# sar_afe_r.lef -- ADC analog front end hard macro (generated 2026-10-20)
# Generated by analog/cadence/pv/macro/export_macro.sh; do not edit.
VERSION 5.8 ;
BUSBITCHARS "[]" ;
DIVIDERCHAR "/" ;

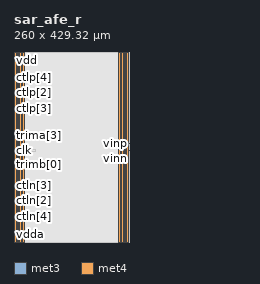
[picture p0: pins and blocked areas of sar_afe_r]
MACRO sar_afe_r
  CLASS BLOCK ;
  FOREIGN sar_afe_r 0 0 ;
  ORIGIN 0 0 ;
  SIZE 260.000 BY 429.320 ;
  SYMMETRY X Y ;
  PIN clk
    DIRECTION INPUT ;
    USE SIGNAL ;
    ANTENNAGATEAREA 1.5000 ;
    PORT
      LAYER met3 ;
        RECT 0.000 206.860 0.600 207.260 ;
    END
  END clk
  PIN ctln[0]
    DIRECTION INPUT ;
    USE SIGNAL ;
    ANTENNAGATEAREA 0.1455 ;
    PORT
      LAYER met3 ;
        RECT 0.000 101.460 0.600 101.860 ;
    END
  END ctln[0]
  PIN ctln[1]
    DIRECTION INPUT ;
    USE SIGNAL ;
    ANTENNAGATEAREA 0.1455 ;
    PORT
      LAYER met3 ;
        RECT 0.000 100.100 0.600 100.500 ;
    END
  END ctln[1]
  PIN ctln[2]
    DIRECTION INPUT ;
    USE SIGNAL ;
    ANTENNAGATEAREA 0.1455 ;
    PORT
      LAYER met3 ;
        RECT 0.000 92.620 0.600 93.020 ;
    END
  END ctln[2]
  PIN ctln[3]
    DIRECTION INPUT ;
    USE SIGNAL ;
    ANTENNAGATEAREA 0.1455 ;
    PORT
      LAYER met3 ;
        RECT 0.000 108.940 0.600 109.340 ;
    END
  END ctln[3]
  PIN ctln[4]
    DIRECTION INPUT ;
    USE SIGNAL ;
    ANTENNAGATEAREA 0.1455 ;
    PORT
      LAYER met3 ;
        RECT 0.000 75.620 0.600 76.020 ;
    END
  END ctln[4]
  PIN ctln[5]
    DIRECTION INPUT ;
    USE SIGNAL ;
    ANTENNAGATEAREA 0.1455 ;
    PORT
      LAYER met3 ;
        RECT 0.000 117.100 0.600 117.500 ;
    END
  END ctln[5]
  PIN ctln[6]
    DIRECTION INPUT ;
    USE SIGNAL ;
    ANTENNAGATEAREA 0.1455 ;
    PORT
      LAYER met3 ;
        RECT 0.000 125.940 0.600 126.340 ;
    END
  END ctln[6]
  PIN ctln[7]
    DIRECTION INPUT ;
    USE SIGNAL ;
    ANTENNAGATEAREA 0.1455 ;
    PORT
      LAYER met3 ;
        RECT 0.000 134.780 0.600 135.180 ;
    END
  END ctln[7]
  PIN ctlp[0]
    DIRECTION INPUT ;
    USE SIGNAL ;
    ANTENNAGATEAREA 0.1455 ;
    PORT
      LAYER met3 ;
        RECT 0.000 327.900 0.600 328.300 ;
    END
  END ctlp[0]
  PIN ctlp[1]
    DIRECTION INPUT ;
    USE SIGNAL ;
    ANTENNAGATEAREA 0.1455 ;
    PORT
      LAYER met3 ;
        RECT 0.000 329.260 0.600 329.660 ;
    END
  END ctlp[1]
  PIN ctlp[2]
    DIRECTION INPUT ;
    USE SIGNAL ;
    ANTENNAGATEAREA 0.1455 ;
    PORT
      LAYER met3 ;
        RECT 0.000 336.740 0.600 337.140 ;
    END
  END ctlp[2]
  PIN ctlp[3]
    DIRECTION INPUT ;
    USE SIGNAL ;
    ANTENNAGATEAREA 0.1455 ;
    PORT
      LAYER met3 ;
        RECT 0.000 319.740 0.600 320.140 ;
    END
  END ctlp[3]
  PIN ctlp[4]
    DIRECTION INPUT ;
    USE SIGNAL ;
    ANTENNAGATEAREA 0.1455 ;
    PORT
      LAYER met3 ;
        RECT 0.000 353.060 0.600 353.460 ;
    END
  END ctlp[4]
  PIN ctlp[5]
    DIRECTION INPUT ;
    USE SIGNAL ;
    ANTENNAGATEAREA 0.1455 ;
    PORT
      LAYER met3 ;
        RECT 0.000 311.580 0.600 311.980 ;
    END
  END ctlp[5]
  PIN ctlp[6]
    DIRECTION INPUT ;
    USE SIGNAL ;
    ANTENNAGATEAREA 0.1455 ;
    PORT
      LAYER met3 ;
        RECT 0.000 302.740 0.600 303.140 ;
    END
  END ctlp[6]
  PIN ctlp[7]
    DIRECTION INPUT ;
    USE SIGNAL ;
    ANTENNAGATEAREA 0.1455 ;
    PORT
      LAYER met3 ;
        RECT 0.000 293.900 0.600 294.300 ;
    END
  END ctlp[7]
  PIN outn
    DIRECTION OUTPUT ;
    USE SIGNAL ;
    ANTENNAGATEAREA 0.6000 ;
    ANTENNADIFFAREA 0.7950 ;
    PORT
      LAYER met3 ;
        RECT 0.000 217.740 0.600 218.140 ;
    END
  END outn
  PIN outp
    DIRECTION OUTPUT ;
    USE SIGNAL ;
    ANTENNAGATEAREA 0.6000 ;
    ANTENNADIFFAREA 0.7950 ;
    PORT
      LAYER met3 ;
        RECT 0.000 211.620 0.600 212.020 ;
    END
  END outp
  PIN sample
    DIRECTION INPUT ;
    USE SIGNAL ;
    ANTENNAGATEAREA 0.5110 ;
    PORT
      LAYER met3 ;
        RECT 0.000 253.100 0.600 253.500 ;
    END
  END sample
  PIN trima[0]
    DIRECTION INPUT ;
    USE SIGNAL ;
    ANTENNAGATEAREA 0.3000 ;
    PORT
      LAYER met3 ;
        RECT 0.000 236.780 0.600 237.180 ;
    END
  END trima[0]
  PIN trima[1]
    DIRECTION INPUT ;
    USE SIGNAL ;
    ANTENNAGATEAREA 0.3000 ;
    PORT
      LAYER met3 ;
        RECT 0.000 238.140 0.600 238.540 ;
    END
  END trima[1]
  PIN trima[2]
    DIRECTION INPUT ;
    USE SIGNAL ;
    ANTENNAGATEAREA 0.3000 ;
    PORT
      LAYER met3 ;
        RECT 0.000 239.500 0.600 239.900 ;
    END
  END trima[2]
  PIN trima[3]
    DIRECTION INPUT ;
    USE SIGNAL ;
    ANTENNAGATEAREA 0.3000 ;
    PORT
      LAYER met3 ;
        RECT 0.000 240.860 0.600 241.260 ;
    END
  END trima[3]
  PIN trima[4]
    DIRECTION INPUT ;
    USE SIGNAL ;
    ANTENNAGATEAREA 0.3000 ;
    PORT
      LAYER met3 ;
        RECT 0.000 242.220 0.600 242.620 ;
    END
  END trima[4]
  PIN trimb[0]
    DIRECTION INPUT ;
    USE SIGNAL ;
    ANTENNAGATEAREA 0.3000 ;
    PORT
      LAYER met3 ;
        RECT 0.000 191.900 0.600 192.300 ;
    END
  END trimb[0]
  PIN trimb[1]
    DIRECTION INPUT ;
    USE SIGNAL ;
    ANTENNAGATEAREA 0.3000 ;
    PORT
      LAYER met3 ;
        RECT 0.000 190.540 0.600 190.940 ;
    END
  END trimb[1]
  PIN trimb[2]
    DIRECTION INPUT ;
    USE SIGNAL ;
    ANTENNAGATEAREA 0.3000 ;
    PORT
      LAYER met3 ;
        RECT 0.000 189.180 0.600 189.580 ;
    END
  END trimb[2]
  PIN trimb[3]
    DIRECTION INPUT ;
    USE SIGNAL ;
    ANTENNAGATEAREA 0.3000 ;
    PORT
      LAYER met3 ;
        RECT 0.000 187.820 0.600 188.220 ;
    END
  END trimb[3]
  PIN trimb[4]
    DIRECTION INPUT ;
    USE SIGNAL ;
    ANTENNAGATEAREA 0.3000 ;
    PORT
      LAYER met3 ;
        RECT 0.000 186.460 0.600 186.860 ;
    END
  END trimb[4]
  PIN vdd
    DIRECTION INOUT ;
    USE POWER ;
    PORT
      LAYER met4 ;
        RECT 19.000 0.000 23.000 429.320 ;
    END
    PORT
      LAYER met4 ;
        RECT 237.000 0.000 241.000 429.320 ;
    END
  END vdd
  PIN vdda
    DIRECTION INOUT ;
    USE POWER ;
    PORT
      LAYER met4 ;
        RECT 7.000 0.000 11.000 429.320 ;
    END
    PORT
      LAYER met4 ;
        RECT 249.000 0.000 253.000 429.320 ;
    END
  END vdda
  PIN vinn
    DIRECTION INPUT ;
    USE SIGNAL ;
    ANTENNADIFFAREA 0.5300 ;
    PORT
      LAYER met3 ;
        RECT 259.400 207.310 260.000 207.710 ;
    END
  END vinn
  PIN vinp
    DIRECTION INPUT ;
    USE SIGNAL ;
    ANTENNADIFFAREA 0.5300 ;
    PORT
      LAYER met3 ;
        RECT 259.400 221.610 260.000 222.010 ;
    END
  END vinp
  PIN vref
    DIRECTION INOUT ;
    USE POWER ;
    PORT
      LAYER met4 ;
        RECT 13.000 0.000 17.000 429.320 ;
    END
    PORT
      LAYER met4 ;
        RECT 243.000 0.000 247.000 429.320 ;
    END
  END vref
  PIN vss
    DIRECTION INOUT ;
    USE GROUND ;
    PORT
      LAYER met4 ;
        RECT 1.000 0.000 5.000 429.320 ;
    END
    PORT
      LAYER met4 ;
        RECT 255.000 0.000 259.000 429.320 ;
    END
  END vss
  OBS
    LAYER li1 ;
      RECT 0.000 0.000 260.000 429.320 ;
    LAYER met1 ;
      RECT 0.000 0.000 260.000 429.320 ;
    LAYER met2 ;
      RECT 0.000 0.000 260.000 429.320 ;
    LAYER met3 ;
      RECT 0.000 0.000 260.000 75.620 ;
      RECT 0.600 75.620 260.000 76.020 ;
      RECT 0.000 76.020 260.000 92.620 ;
      RECT 0.600 92.620 260.000 93.020 ;
      RECT 0.000 93.020 260.000 100.100 ;
      RECT 0.600 100.100 260.000 100.500 ;
      RECT 0.000 100.500 260.000 101.460 ;
      RECT 0.600 101.460 260.000 101.860 ;
      RECT 0.000 101.860 260.000 108.940 ;
      RECT 0.600 108.940 260.000 109.340 ;
      RECT 0.000 109.340 260.000 117.100 ;
      RECT 0.600 117.100 260.000 117.500 ;
      RECT 0.000 117.500 260.000 125.940 ;
      RECT 0.600 125.940 260.000 126.340 ;
      RECT 0.000 126.340 260.000 134.780 ;
      RECT 0.600 134.780 260.000 135.180 ;
      RECT 0.000 135.180 260.000 186.460 ;
      RECT 0.600 186.460 260.000 186.860 ;
      RECT 0.000 186.860 260.000 187.820 ;
      RECT 0.600 187.820 260.000 188.220 ;
      RECT 0.000 188.220 260.000 189.180 ;
      RECT 0.600 189.180 260.000 189.580 ;
      RECT 0.000 189.580 260.000 190.540 ;
      RECT 0.600 190.540 260.000 190.940 ;
      RECT 0.000 190.940 260.000 191.900 ;
      RECT 0.600 191.900 260.000 192.300 ;
      RECT 0.000 192.300 260.000 206.860 ;
      RECT 0.600 206.860 260.000 207.260 ;
      RECT 0.000 207.260 260.000 207.310 ;
      RECT 0.000 207.310 259.400 207.710 ;
      RECT 0.000 207.710 260.000 211.620 ;
      RECT 0.600 211.620 260.000 212.020 ;
      RECT 0.000 212.020 260.000 217.740 ;
      RECT 0.600 217.740 260.000 218.140 ;
      RECT 0.000 218.140 260.000 221.610 ;
      RECT 0.000 221.610 259.400 222.010 ;
      RECT 0.000 222.010 260.000 236.780 ;
      RECT 0.600 236.780 260.000 237.180 ;
      RECT 0.000 237.180 260.000 238.140 ;
      RECT 0.600 238.140 260.000 238.540 ;
      RECT 0.000 238.540 260.000 239.500 ;
      RECT 0.600 239.500 260.000 239.900 ;
      RECT 0.000 239.900 260.000 240.860 ;
      RECT 0.600 240.860 260.000 241.260 ;
      RECT 0.000 241.260 260.000 242.220 ;
      RECT 0.600 242.220 260.000 242.620 ;
      RECT 0.000 242.620 260.000 253.100 ;
      RECT 0.600 253.100 260.000 253.500 ;
      RECT 0.000 253.500 260.000 293.900 ;
      RECT 0.600 293.900 260.000 294.300 ;
      RECT 0.000 294.300 260.000 302.740 ;
      RECT 0.600 302.740 260.000 303.140 ;
      RECT 0.000 303.140 260.000 311.580 ;
      RECT 0.600 311.580 260.000 311.980 ;
      RECT 0.000 311.980 260.000 319.740 ;
      RECT 0.600 319.740 260.000 320.140 ;
      RECT 0.000 320.140 260.000 327.900 ;
      RECT 0.600 327.900 260.000 328.300 ;
      RECT 0.000 328.300 260.000 329.260 ;
      RECT 0.600 329.260 260.000 329.660 ;
      RECT 0.000 329.660 260.000 336.740 ;
      RECT 0.600 336.740 260.000 337.140 ;
      RECT 0.000 337.140 260.000 353.060 ;
      RECT 0.600 353.060 260.000 353.460 ;
      RECT 0.000 353.460 260.000 429.320 ;
    LAYER met4 ;
      RECT 0.000 0.000 1.000 429.320 ;
      RECT 5.000 0.000 7.000 429.320 ;
      RECT 11.000 0.000 13.000 429.320 ;
      RECT 17.000 0.000 19.000 429.320 ;
      RECT 23.000 0.000 237.000 429.320 ;
      RECT 241.000 0.000 243.000 429.320 ;
      RECT 247.000 0.000 249.000 429.320 ;
      RECT 253.000 0.000 255.000 429.320 ;
      RECT 259.000 0.000 260.000 429.320 ;
    LAYER met5 ;
      RECT 25.370 204.175 49.510 209.775 ;
  END
END sar_afe_r

END LIBRARY
